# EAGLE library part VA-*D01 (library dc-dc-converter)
DC DC Converter Dual Separate Output, 1 Watt Motien Technology Co.,Ltd. Source: VA-D01.pdf

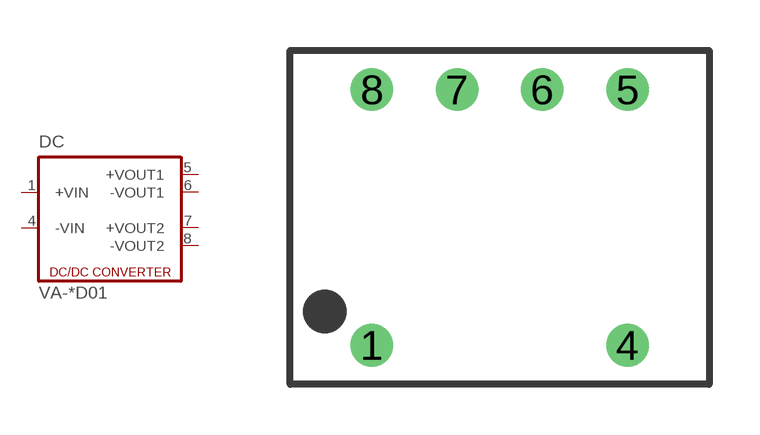
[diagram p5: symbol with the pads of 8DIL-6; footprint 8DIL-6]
Designator prefix DC

## VA-0505D01, VA-0509D01, VA-0512D01, VA-0515D01, VA-0524D01, VA-1205D01, VA-1209D01, VA-1212D01, VA-1215D01, VA-1224D01, VA-2405D01, VA-2409D01, VA-2412D01, VA-2415D01, VA-2424D01  [8DIL-6]
1  +VIN  pas
4  -VIN  pas
5  +VOUT1  pas
6  -VOUT1  pas
7  +VOUT2  pas
8  -VOUT2  pas

## Footprint 8DIL-6 (pad centres in mm)
8 DIL Package 6 Pads Motien Technology Co.,Ltd. Source: VA-D01.pdf
drill 0.7 pad 1.27 round: 1 -3.81,-3.81; 4 3.81,-3.81; 5 3.81,3.81; 6 1.27,3.81; 7 -1.27,3.81; 8 -3.81,3.81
